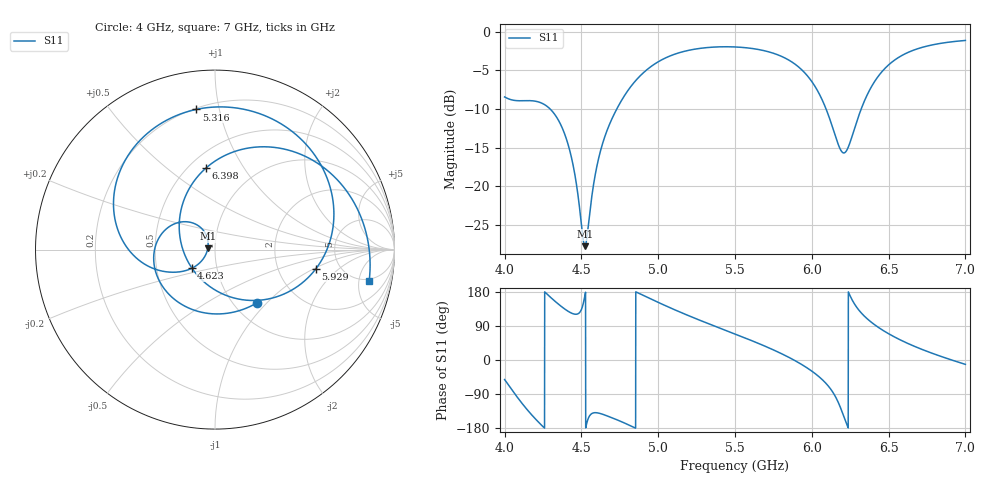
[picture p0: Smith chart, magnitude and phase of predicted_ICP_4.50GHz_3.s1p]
! ICP-predicted S11, target max centred GHz at -10 dB. Complex ensemble mean (passive and causal);
! its |S11| can differ slightly from the dB-domain mean reported in designs.csv.
!  Air_gap = 2.49mm
!  W_Patch = 12.3mm
!  L_Patch = 20.97mm
!  Sx = 0.73mm
!  Sy = 4.3mm
!  W_Patch1 = 15.75mm
!  WS = 1.22mm
!  Curve_Amp1 = 3.39mm
!  Extra = 5.18mm
# GHz S MA R 50
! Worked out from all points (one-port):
!   3001 points, 4 GHz to 7 GHz, reference 50 ohm
!   lowest |S11| = -27.8 dB at 4.523 GHz (marker M1), VSWR 1.09, Z = 46.1 + j0.623 ohm
!   |S11| at or under -10 dB: 4.296 GHz to 4.731 GHz (435.1 MHz wide, 9.64 % of centre); 6.093 GHz to 6.322 GHz (229.2 MHz wide, 3.69 % of centre)
!   S11 on the Smith chart (normalised r, x): 4 GHz: 1.27, -0.88; 4.623 GHz: 0.75, -0.16; 5.316 GHz: 0.21, +0.85; 5.929 GHz: 3.33, -1.04; 6.398 GHz: 0.60, +0.69; 7 GHz: 4.57, -6.93
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4  0.3778 -51.6
4.091  0.357 -102.7
4.197  0.355 -153.9
4.275  0.3293 174.4
4.375  0.2383 139.5
4.446  0.1365 122.0
4.523  0.04088 170.5
4.585  0.1111 -139.1
4.623  0.1672 -141.3
4.75  0.3429 -160.9
4.84  0.4649 -177.4
4.947  0.5883 162.0
5.125  0.7241 129.4
5.316  0.7879 97.6
5.5  0.7958 68.6
5.71  0.7442 33.9
5.875  0.6317 1.8
5.929  0.573 -10.6
6.017  0.4484 -34.4
6.092  0.3173 -61.5
6.193  0.1682 -132.2
6.25  0.193 168.8
6.32  0.3127 125.2
6.398  0.4568 96.4
6.505  0.6152 68.2
6.625  0.7323 43.7
6.804  0.8279 14.8
7  0.8767 -11.5
